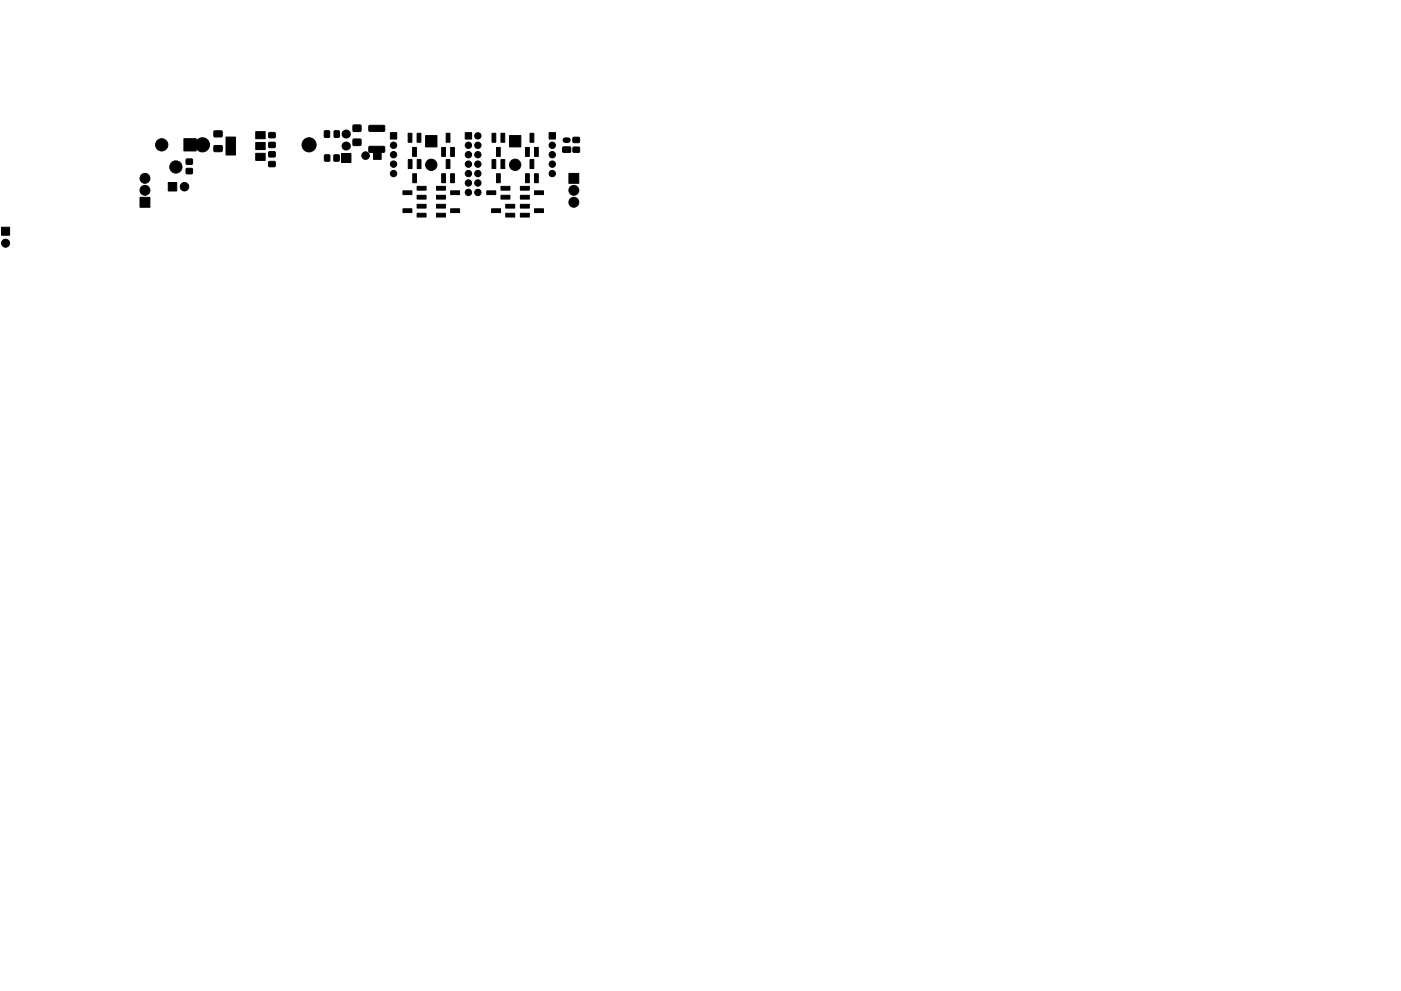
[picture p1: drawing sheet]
<svg xmlns="http://www.w3.org/2000/svg" width="297mm" height="210mm" viewBox="0 0 297 210" stroke-linecap="round" stroke-linejoin="round" font-family="sans-serif">
<g fill="#000" stroke="#000" stroke-width=".21">
<path d="M39 29.4h2.6v2.6h-2.6zM39.5 35.8h1.2l.1 1h-1.3zM39.5 33.8h1.2l.1 1h-1.3zM45.4 27.8h1.6l.1 1.2h-1.7zM45.4 30.9h1.6l.1 1.2h-1.7zM47.9 29.1h2v3.8h-2zM54.2 27.9h2v1.5h-2zM54.2 32.5h2v1.5h-2zM54.2 30.2h2v1.5h-2zM57 28.2l1.3-.1v1.1h-1.3zM57 30.2h1.3v1l-1.3 .1zM57 32.2h1.3v1l-1.3 .1z"/>
<path d="M57 34.3h1.3v1h-1.3zM68.8 27.8h1.1l-.1 1.3h-1zM68.8 32.9h1.1v1.3l-1.1-.1zM70.8 32.9h1.1v1.3l-1.1-.1zM70.9 27.8h1v1.3h-1zM72.4 32.6h2v1.9h-2zM74.9 29.5h1.6v1.3h-1.6zM74.9 26.6h1.6v1.2l-1.6 .1zM79.2 32.2h1.6v1.6h-1.6zM78.3 26.7l3.1-.1 .2 .2v.9l-.3 .2h-2.9l-.2-.2zM78.3 31.1l3.1-.1 .2 .2v1l-.3 .1h-2.9l-.2-.2zM82.8 28.1h1.3v1.4h-1.3z"/>
<path d="M86.5 28.3h.8v1.9h-.8zM86.6 33.9h.8v1.9h-.8zM87.5 31.3h.8v1.9h-.8zM87.5 36.9h.8v1.9h-.8zM88.4 28.3h.8v1.9h-.8zM88.5 33.9h.8v1.9h-.8zM90.2 28.8h2.4v2.4h-2.4zM88.4 39.5h1.9v.8h-1.9zM93.6 31.3h.8v1.9h-.8zM93.6 36.9h.8v1.9h-.8zM94.6 28.3h.8v1.9h-.8zM94.6 33.9h.8v1.9h-.8z"/>
<path d="M95.5 31.3h.8v1.9h-.8zM95.5 36.9h.8v1.9h-.8zM98.6 28.1h1.4v1.4h-1.4zM104.3 28.3h.8v1.9h-.8zM104.3 33.9h.8v1.9h-.8zM105.3 31.3h.8v1.9h-.8zM105.3 36.9h.8v1.9h-.8zM106.2 28.3h.8v1.9h-.8zM106.2 33.9h.8v1.9h-.8zM108 28.8h2.4v2.4h-2.4zM106.2 39.5h1.9v.8h-1.9zM111.4 31.3h.8v1.9h-.8z"/>
<path d="M111.4 36.9h.8v1.9h-.8zM112.4 28.3h.8v1.9h-.8zM112.4 33.9h.8v1.9h-.8zM113.3 31.3h.8v1.9h-.8zM113.3 36.9h.8v1.9h-.8zM116.4 28.1h1.4v1.4h-1.4zM120.6 36.8h2.1v2.1h-2.1zM119.3 31.2h1.6l.1 1-1.6 .1zM121.5 31.3l1.3-.1v1.1h-1.3zM121.5 29.2h1.3v1h-1.3zM.3 48.2h1.7v1.7h-1.7zM29.7 41.9h2.1v2.1h-2.1z"/>
<path d="M35.7 38.7h1.8v1.8h-1.8zM85.4 44.3h1.9v.8h-1.9zM85.4 40.5h1.9v.8h-1.9zM88.4 45.2h1.9v.8h-1.9zM88.4 43.3h1.9v.8h-1.9zM88.4 41.4h1.9v.8h-1.9zM92.5 43.3h1.9v.8h-1.9zM92.5 45.2h1.9v.8h-1.9zM92.5 39.5h1.9v.8h-1.9zM92.5 41.4h1.9v.8h-1.9zM95.5 44.3h1.9v.8h-1.9zM95.5 40.5h1.9v.8h-1.9z"/>
<path d="M103.2 40.5h1.9v.8h-1.9zM104.2 44.3h1.9v.8h-1.9zM106.2 41.4h1.9v.8h-1.9zM107.2 45.2h1.9v.8h-1.9zM107.2 43.3h1.9v.8h-1.9zM110.3 43.3h1.9v.8h-1.9zM110.3 45.2h1.9v.8h-1.9zM110.3 39.5h1.9v.8h-1.9zM110.3 41.4h1.9v.8h-1.9zM113.3 44.3h1.9v.8h-1.9zM113.3 40.5h1.9v.8h-1.9z"/>
<circle cx="30.7" cy="37.8" r="1.05"/>
<circle cx="34.3" cy="30.7" r="1.3"/>
<circle cx="37.3" cy="35.4" r="1.3"/>
<circle cx="39.1" cy="39.6" r=".9"/>
<circle cx="42.9" cy="30.7" r="1.5"/>
<circle cx="65.5" cy="30.7" r="1.5"/>
<circle cx="77.5" cy="33" r=".8"/>
<circle cx="83.4" cy="30.8" r=".67"/>
<circle cx="83.4" cy="32.8" r=".67"/>
<circle cx="83.4" cy="34.8" r=".67"/>
<circle cx="83.4" cy="36.8" r=".67"/>
<circle cx="91.4" cy="35" r="1.2"/>
<circle cx="99.3" cy="30.8" r=".67"/>
<circle cx="99.3" cy="32.8" r=".67"/>
<circle cx="99.3" cy="34.8" r=".67"/>
<circle cx="99.3" cy="38.8" r=".67"/>
<circle cx="99.3" cy="36.8" r=".67"/>
<circle cx="101.3" cy="30.8" r=".67"/>
<circle cx="101.3" cy="28.8" r=".67"/>
<circle cx="101.3" cy="32.8" r=".67"/>
<circle cx="101.3" cy="34.8" r=".67"/>
<circle cx="101.3" cy="38.8" r=".67"/>
<circle cx="101.3" cy="36.8" r=".67"/>
<circle cx="109.2" cy="35" r="1.2"/>
<circle cx="117.1" cy="30.8" r=".67"/>
<circle cx="117.1" cy="32.8" r=".67"/>
<circle cx="117.1" cy="34.8" r=".67"/>
<circle cx="117.1" cy="36.8" r=".67"/>
<circle cx="1.2" cy="51.6" r=".85"/>
<circle cx="30.7" cy="40.4" r="1.05"/>
<circle cx="99.3" cy="40.8" r=".67"/>
<circle cx="101.3" cy="40.8" r=".67"/>
<circle cx="121.7" cy="42.9" r="1.05"/>
<circle cx="121.7" cy="40.4" r="1.05"/>
</g>
<path d="M73.4 28.4h.1M73.4 31h.1" fill="none" stroke="#000" stroke-width="1.9"/>
<path d="M119.9 29.7h.5" fill="none" stroke="#000" stroke-width="1.2"/>
</svg>
